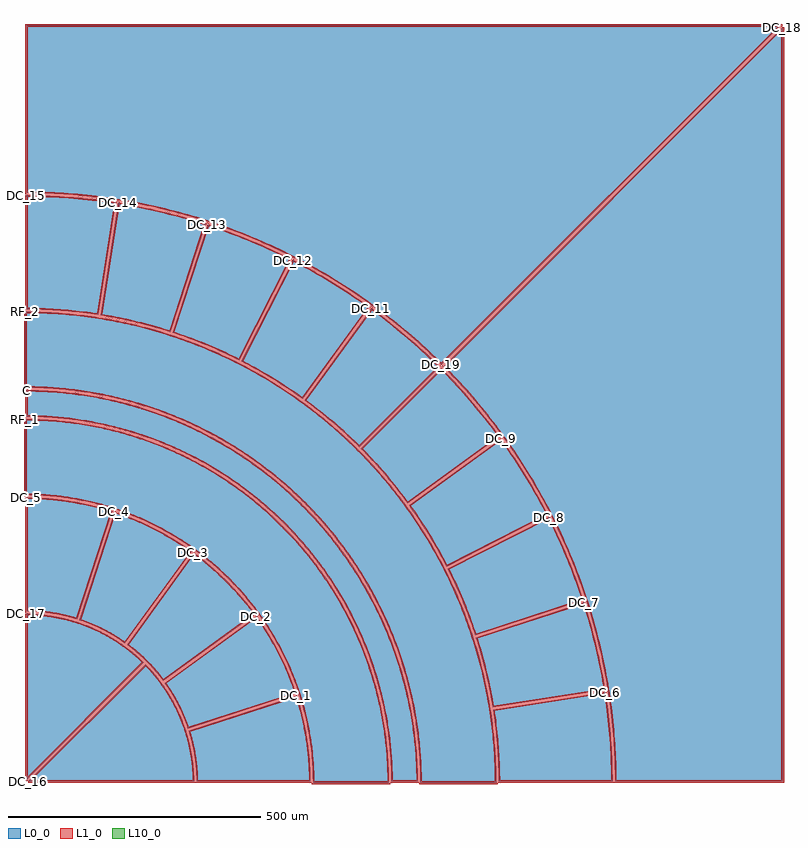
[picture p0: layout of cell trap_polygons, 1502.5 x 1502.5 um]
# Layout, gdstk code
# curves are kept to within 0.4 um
import gdstk
lib = gdstk.Library(unit=1e-6, precision=1e-09)
def P(c, l, *ps):  # polygons
    for p in ps: c.add(gdstk.Polygon(p, *l))
L0_0 = (0, 0)
L1_0 = (1, 0)
L10_0 = (10, 0)

trap_polygons = lib.new_cell('trap_polygons')
P(trap_polygons, L0_0, [(822.805,826.341),(782.779,864.352),(740.999,900.427),(712.217,923.36),(690.164,939.958),(644.909,971.565),(598.21,1000.996),(550.171,1028.183),(525.682,1040.916),(492.574,1056.986),(442.003,1079.111),(390.442,1098.819),(338.006,1116.064),(311.496,1123.752),(275.881,1133.021),(221.955,1144.807),(167.531,1154.028),(112.732,1160.663),(57.681,1164.698),(2.5,1166.122),(2.5,1497.5),(1493.964,1497.5)],
  [(1497.5,1493.964),(1497.5,2.5),(1166.122,2.5),(1164.698,57.681),(1160.663,112.732),(1154.028,167.531),(1144.807,221.955),(1133.021,275.881),(1123.752,311.496),(1116.064,338.006),(1098.819,390.442),(1079.111,442.003),(1056.986,492.574),(1040.916,525.682),(1028.183,550.171),(1000.996,598.21),(971.565,644.909),(939.958,690.164),(923.36,712.217),(900.427,740.999),(864.352,782.779),(826.341,822.805)],
  [(2.5,333.866),(33.622,332.178),(49.09,330.246),(66.998,327.084),(84.707,322.951),(99.689,318.645),(128.968,307.961),(157.123,294.593),(183.909,278.658),(209.092,260.294),(222.954,248.524),(234.311,237.846),(2.5,6.036)],
  [(6.036,2.5),(237.846,234.311),(248.524,222.954),(260.294,209.092),(278.658,183.909),(294.593,157.123),(307.961,128.968),(318.645,99.689),(322.951,84.707),(327.084,66.998),(330.246,49.09),(332.178,33.622),(333.866,2.5)],
  [(2.5,1161.122),(49.167,1160.084),(86.446,1157.903),(132.916,1153.492),(179.17,1147.218),(143.972,924.988),(106.932,929.998),(77.173,932.939),(39.869,935.276),(2.5,936.122)],
  [(184.109,1146.436),(220.88,1139.923),(266.518,1130.124),(311.725,1118.498),(356.429,1105.065),(286.9,891.077),(258.293,899.786),(222.167,909.38),(185.687,917.524),(148.911,924.205)],
  [(361.184,1103.52),(405.246,1088.112),(448.652,1070.945),(491.334,1052.047),(524.911,1035.703),(422.763,835.225),(389.083,851.437),(354.783,866.29),(319.918,879.763),(291.655,889.532)],
  [(529.366,1033.433),(570.475,1011.321),(602.701,992.453),(642.103,967.427),(680.468,940.837),(548.216,758.808),(517.487,780.088),(485.933,800.125),(460.129,815.237),(427.218,832.956)],
  [(684.513,937.898),(721.657,909.628),(757.634,879.888),(785.537,855.069),(819.27,822.805),(660.17,663.706),(638.635,684.453),(610.802,709.402),(581.996,733.22),(552.261,755.869)],
  [(822.805,819.27),(855.069,785.537),(879.888,757.634),(909.628,721.657),(937.898,684.513),(755.869,552.261),(733.22,581.996),(709.402,610.802),(684.453,638.635),(663.706,660.17)],
  [(940.837,680.468),(967.427,642.103),(992.453,602.701),(1011.321,570.475),(1033.433,529.366),(832.956,427.218),(815.237,460.129),(800.125,485.933),(780.088,517.487),(758.808,548.216)],
  [(1035.703,524.911),(1052.047,491.334),(1070.945,448.652),(1088.112,405.246),(1103.52,361.184),(889.532,291.655),(879.763,319.918),(866.29,354.783),(851.437,389.083),(835.225,422.763)],
  [(1105.065,356.429),(1118.498,311.725),(1130.124,266.518),(1139.923,220.88),(1146.436,184.109),(924.205,148.911),(917.524,185.687),(909.38,222.167),(899.786,258.293),(891.077,286.9)],
  [(1147.218,179.17),(1153.492,132.916),(1157.903,86.446),(1160.084,49.167),(1161.122,2.5),(936.122,2.5),(935.276,39.869),(932.939,77.173),(929.998,106.932),(924.988,143.972)],
  [(2.5,563.869),(42.187,562.295),(64.157,560.213),(86.029,557.274),(107.769,553.481),(129.344,548.84),(150.721,543.358),(171.868,537.044),(102.338,323.053),(77.26,329.95),(51.727,334.904),(25.889,337.885),(2.5,338.866)],
  [(176.623,535.499),(213.881,521.738),(234.132,512.969),(254.025,503.414),(273.53,493.089),(292.615,482.008),(311.251,470.189),(329.412,457.649),(197.158,275.618),(175.439,289.927),(155.004,301.347),(131.436,312.348),(107.093,321.508)],
  [(333.457,454.711),(350.994,441.314),(367.994,427.242),(397.156,400.277),(412.515,384.43),(427.242,367.994),(441.314,350.994),(454.711,333.457),(272.679,201.203),(258.137,219.548),(240.539,238.699),(221.523,256.444),(201.203,272.679)],
  [(457.649,329.412),(470.189,311.251),(482.008,292.615),(493.089,273.53),(503.414,254.025),(512.969,234.132),(521.738,213.881),(535.499,176.623),(321.508,107.093),(312.348,131.436),(301.347,155.004),(289.927,175.439),(275.618,197.158)],
  [(537.044,171.868),(543.358,150.721),(548.84,129.344),(553.481,107.769),(557.274,86.029),(560.213,64.157),(562.295,42.187),(563.869,2.5),(338.866,2.5),(337.885,25.889),(334.904,51.727),(329.95,77.26),(323.053,102.338)],
  [(2.5,776.121),(38.908,775.149),(75.23,772.47),(111.386,768.091),(153.253,760.844),(188.778,752.817),(223.887,743.132),(264.22,729.766),(298.165,716.567),(331.453,701.79),(364.011,685.468),(400.978,664.52),(431.711,644.977),(461.494,624.014),(490.261,601.676),(517.948,578.014),(548.803,548.803),(578.014,517.948),(601.676,490.261),(624.014,461.494),(644.977,431.711),(664.52,400.978),(685.468,364.011),(701.79,331.453),(716.567,298.165),(729.766,264.22),(743.132,223.887),(752.817,188.778),(760.844,153.253),(768.091,111.386),(772.47,75.23),(775.149,38.908),(776.121,2.5),(723.871,2.5),(722.957,36.446),(720.452,70.313),(716.362,104.024),(709.598,143.06),(702.108,176.182),(693.072,208.916),(680.605,246.521),(668.294,278.169),(654.513,309.206),(639.291,339.562),(622.662,369.171),(601.533,402.683),(581.985,430.451),(561.157,457.272),(535.299,487.288),(511.857,511.857),(487.288,535.299),(457.272,561.157),(430.451,581.985),(402.683,601.533),(369.171,622.662),(339.562,639.291),(309.206,654.513),(278.169,668.294),(246.521,680.605),(208.916,693.072),(176.182,702.108),(143.06,709.598),(104.024,716.362),(70.313,720.452),(36.446,722.957),(2.5,723.871)],
  [(0,931.125),(43.862,930.091),(87.627,926.993),(131.197,921.836),(181.653,913.234),(224.471,903.663),(266.79,892.086),(315.407,876.078),(356.326,860.247),(396.454,842.507),(442.151,819.449),(480.261,797.711),(517.305,774.202),(553.201,748.974),(593.521,717.444),(626.659,688.689),(658.405,658.405),(688.689,626.659),(717.444,593.521),(748.974,553.201),(774.202,517.305),(797.711,480.261),(819.449,442.151),(842.507,396.454),(860.247,356.326),(876.078,315.407),(892.086,266.79),(903.663,224.471),(913.234,181.653),(921.836,131.197),(926.993,87.627),(930.091,43.862),(931.125,0),(781.125,0),(779.945,42.923),(777.057,79.616),(772.444,116.132),(766.116,152.39),(758.087,188.31),(748.375,223.811),(737.001,258.816),(721.665,298.924),(706.783,332.587),(690.331,365.512),(672.347,397.625),(649.482,433.97),(628.318,464.083),(601.867,497.908),(577.744,525.707),(552.339,552.339),(525.707,577.744),(497.908,601.867),(464.083,628.318),(433.97,649.482),(397.625,672.347),(365.512,690.331),(332.587,706.783),(298.924,721.665),(258.816,737.001),(223.811,748.375),(188.31,758.087),(152.39,766.116),(116.132,772.444),(79.616,777.057),(42.923,779.945),(0,781.125)],
  [(0,718.875),(33.864,718.077),(67.652,715.685),(106.877,710.886),(140.246,705.062),(173.303,697.673),(205.975,688.735),(243.51,676.376),(275.102,664.154),(306.082,650.458),(341.362,632.656),(370.786,615.873),(399.386,597.723),(427.099,578.246),(453.864,557.485),(479.621,535.486),(508.321,508.321),(535.486,479.621),(557.485,453.864),(578.246,427.099),(597.723,399.386),(615.873,370.786),(632.656,341.362),(650.458,306.082),(664.154,275.102),(676.376,243.51),(688.735,205.975),(697.673,173.303),(705.062,140.246),(710.886,106.877),(715.685,67.652),(718.077,33.864),(718.875,0),(568.875,0),(568.436,22.334),(566.753,49.086),(564.389,71.299),(561.155,93.402),(557.055,115.361),(552.097,137.142),(545.024,162.997),(538.204,184.269),(528.927,209.417),(520.297,230.021),(508.884,254.275),(498.509,274.058),(487.365,293.418),(475.47,312.325),(460.23,334.376),(446.747,352.187),(426.719,376.204),(405.402,399.084),(379.544,423.752),(355.685,443.967),(330.751,462.842),(301.037,482.696),(274.058,498.509),(246.25,512.815),(213.565,527.266),(184.269,538.204),(154.416,547.517),(124.096,555.175),(93.402,561.155),(62.425,565.44),(31.26,568.015),(0,568.875)])
P(trap_polygons, L1_0, [(457.992,1075.133),(425.831,1088.279),(399.955,1098.053),(347.544,1115.75),(294.355,1130.946),(240.506,1143.609),(186.119,1153.709),(158.761,1157.791),(122.148,1162.224),(67.012,1166.702),(39.38,1167.961),(5,1168.607),(5,1495),(457.992,1495),(457.992,1500),(0,1500),(0,1163.637),(57.557,1162.201),(112.491,1158.175),(167.172,1151.554),(221.479,1142.353),(248.454,1136.791),(284.202,1128.385),(337.281,1113.672),(363.545,1105.377),(398.244,1093.355),(432.546,1080.244),(457.992,1069.704)],
  [(822.805,826.341),(824.573,824.573),(1497.5,1497.5),(1496.464,1500),(457.992,1500),(457.992,1495),(1487.929,1495),(822.794,829.866),(784.457,866.205),(742.588,902.357),(699.054,936.487),(653.954,968.519),(607.389,998.38),(559.463,1026.005),(510.283,1051.331),(457.992,1075.133),(457.992,1069.704),(508.1,1046.832),(557.069,1021.615),(604.79,994.109),(635.858,974.53),(658.745,959.207),(696.063,932.48),(732.298,904.302),(753.496,886.717),(781.101,862.499),(821.048,824.562)],
  [(1500,451.469),(1495,451.469),(1495,5),(1168.607,5),(1167.961,39.38),(1166.702,67.012),(1164.007,103.793),(1161.224,131.314),(1157.791,158.761),(1152.205,195.215),(1141.676,249.522),(1133.234,285.423),(1123.663,321.04),(1112.973,356.337),(1104.227,382.579),(1091.605,417.232),(1077.896,451.469),(1072.466,451.469),(1093.355,398.244),(1110.976,346.057),(1118.855,319.666),(1128.385,284.202),(1140.57,230.485),(1147.275,194.38),(1151.554,167.172),(1158.175,112.491),(1162.201,57.557),(1163.637,0),(1500,0)],
  [(1500,1493.964),(1497.501,1493.964),(1495.732,1495.732),(822.816,822.816),(862.499,781.101),(898.496,739.41),(932.48,696.063),(964.375,651.156),(994.109,604.79),(1021.615,557.069),(1046.832,508.1),(1058.565,483.181),(1072.466,451.469),(1077.896,451.469),(1059.252,493.63),(1043.148,526.809),(1026.005,559.463),(1012.476,583.589),(993.557,615.247),(978.717,638.59),(947.401,684.19),(925.34,713.744),(908.188,735.445),(872.367,777.599),(853.719,798.028),(829.866,822.795),(1495,1487.929),(1495,451.469),(1500,451.469)],
  [(237.846,237.846),(222.668,252.125),(206.551,265.49),(189.633,277.827),(174.224,287.74),(155.985,298.022),(134.746,308.207),(121.723,308.207),(151.377,294.779),(164.971,287.392),(180.374,277.983),(195.242,267.75),(207.526,258.345),(230.755,237.826),(5,12.071),(5,308.207),(0,308.207),(0,3.536),(2.5,2.5)],
  [(132.344,309.246),(115.31,315.993),(97.934,321.803),(80.267,326.658),(62.363,330.544),(41.677,333.783),(18.216,335.881),(2.528,336.365),(2.5,333.866),(0,333.866),(0,308.207),(5,308.207),(5,331.337),(30.803,329.94),(56.36,326.547),(74.056,322.994),(89.051,319.185),(106.298,313.863),(121.723,308.207),(134.746,308.207)],
  [(237.868,230.712),(258.345,207.526),(267.75,195.242),(277.983,180.374),(287.392,164.971),(294.779,151.377),(307.61,123.229),(307.61,136.097),(298.022,155.985),(287.74,174.224),(277.827,189.633),(265.49,206.551),(252.125,222.668),(237.846,237.846),(4.268,4.268),(6.036,2.499),(6.036,0),(307.61,0),(307.61,5),(12.071,5)],
  [(336.394,0.029),(335.881,18.216),(334.391,36.477),(332.324,52.045),(328.998,70.062),(325.369,85.342),(320.24,102.93),(314.16,120.214),(307.61,136.097),(307.61,123.229),(313.863,106.298),(318.483,91.533),(322.408,76.568),(326.098,58.9),(329.691,33.37),(331.337,5),(307.61,5),(307.61,0)],
  [(2.515,1163.622),(2.485,1158.622),(49.061,1157.586),(86.26,1155.409),(132.63,1151.009),(176.308,1145.125),(141.892,927.831),(107.217,932.481),(77.38,935.43),(39.975,937.773),(5,938.605),(5,1161.122),(0,1161.122),(0,933.638),(32.311,933.066),(69.534,931.032),(106.646,927.514),(146.053,922.144),(182.031,1149.296),(142.492,1154.868),(95.96,1159.662),(49.272,1162.581)],
  [(184.515,1148.903),(183.702,1143.969),(220.404,1137.468),(265.944,1127.69),(311.054,1116.09),(353.274,1103.446),(285.29,894.212),(251.769,904.228),(215.471,913.558),(186.183,919.974),(151.769,926.267),(186.578,1146.045),(181.64,1146.827),(146.053,922.144),(177.877,916.523),(214.324,908.692),(250.428,899.412),(288.51,887.943),(359.579,1106.671),(321.399,1118.359),(276.19,1130.373),(230.534,1140.56)],
  [(361.971,1105.893),(360.397,1101.148),(404.373,1085.769),(439.08,1072.204),(481.819,1053.69),(521.541,1034.596),(421.663,838.573),(390.122,853.71),(355.731,868.604),(327.806,879.523),(294.8,891.121),(363.562,1102.748),(358.807,1104.293),(288.51,887.943),(319.063,877.413),(353.836,863.977),(388.044,849.163),(423.863,831.878),(528.273,1036.795),(492.392,1054.312),(449.618,1073.25),(406.118,1090.455)],
  [(530.515,1035.653),(528.217,1031.212),(561.114,1013.688),(601.403,990.316),(640.721,965.344),(676.967,940.272),(547.653,762.286),(518.869,782.171),(493.622,798.345),(461.358,817.414),(430.573,834.033),(531.594,1032.298),(527.138,1034.568),(423.863,831.878),(458.901,813.06),(490.993,794.092),(522.302,773.858),(548.779,755.329),(683.96,941.39),(651.261,964.304),(611.976,989.701),(571.703,1013.498)],
  [(685.995,939.912),(683.031,935.885),(720.103,907.669),(748.919,884.043),(783.846,853.228),(815.723,822.794),(660.158,667.23),(634.839,691.373),(606.733,716.165),(583.55,735.178),(555.743,756.409),(686.536,936.429),(682.491,939.368),(548.779,755.329),(574.583,735.874),(603.501,712.35),(631.458,687.69),(660.182,660.182),(822.805,822.805),(794.093,850.553),(759.265,881.782),(723.21,911.586)],
  [(824.584,821.027),(821.027,817.513),(846.898,790.681),(877.993,756.003),(907.669,720.103),(934.394,685.057),(756.409,555.743),(735.178,583.55),(716.165,606.733),(691.373,634.839),(667.23,660.158),(824.573,817.502),(821.037,821.037),(660.182,660.182),(687.69,631.458),(712.35,603.501),(735.874,574.583),(755.329,548.779),(941.39,683.96),(917.372,715.857),(887.858,752.151),(856.91,787.228)],
  [(942.869,681.925),(938.806,679.011),(965.344,640.721),(985.448,609.347),(1009.143,569.246),(1030.056,530.452),(834.033,430.573),(817.414,461.358),(798.345,493.622),(782.171,518.869),(762.286,547.653),(942.307,678.445),(939.368,682.491),(755.329,548.779),(773.858,522.302),(794.092,490.993),(813.06,458.901),(831.878,423.863),(1036.795,528.273),(1018.062,563.535),(994.59,603.999),(969.51,643.486)],
  [(1037.937,526.032),(1033.468,523.79),(1053.69,481.819),(1068.639,447.686),(1085.769,404.373),(1100.355,362.784),(891.121,294.8),(879.523,327.806),(868.604,355.731),(853.71,390.122),(838.573,421.663),(1036.838,522.683),(1034.568,527.138),(831.878,423.863),(849.163,388.044),(863.977,353.836),(877.413,319.063),(887.943,288.51),(1106.671,359.579),(1093.685,397.337),(1076.831,440.974),(1058.237,483.899)],
  [(1107.448,357.187),(1102.683,355.671),(1113.553,320.018),(1125.516,275.003),(1135.659,229.543),(1143.56,186.184),(926.267,151.769),(919.974,186.183),(913.558,215.471),(904.228,251.769),(894.212,285.29),(1105.838,354.051),(1104.293,358.807),(887.943,288.51),(899.412,250.428),(908.692,214.324),(916.523,177.877),(922.144,146.053),(1149.296,182.031),(1142.377,221.355),(1132.557,267.092),(1120.907,312.396)],
  [(1149.69,179.546),(1144.746,178.794),(1151.009,132.63),(1154.679,95.548),(1157.586,49.061),(1158.607,5),(938.605,5),(937.773,39.975),(935.43,77.38),(932.481,107.217),(927.831,141.892),(1147.609,176.701),(1146.827,181.64),(922.144,146.053),(927.514,106.646),(931.032,69.534),(933.066,32.311),(933.638,0),(1163.622,0),(1162.94,39.923),(1160.396,86.632),(1155.976,133.202)],
  [(2.521,566.369),(2.479,561.37),(42,559.802),(63.873,557.729),(85.648,554.803),(107.291,551.027),(128.771,546.406),(168.711,535.419),(100.724,326.177),(77.83,332.384),(54.697,336.965),(28.692,340.167),(5,341.338),(5,563.869),(0,563.869),(0,336.394),(28.272,335.185),(53.896,332.029),(79.202,326.918),(103.951,319.929),(175.018,538.649),(134.229,550.239),(112.596,555.07),(90.789,559.051),(68.844,562.175),(46.794,564.439),(24.671,565.837)],
  [(177.415,537.87),(175.831,533.128),(196.566,525.836),(216.992,517.742),(252.899,501.182),(272.317,490.903),(291.317,479.871),(325.907,457.079),(196.588,279.087),(176.733,292.066),(153.812,304.76),(132.405,314.652),(110.234,323.087),(179.001,534.727),(174.245,536.272),(103.951,319.929),(130.466,310.043),(153.86,299.124),(176.349,286.443),(197.727,272.148),(332.904,458.203),(297.693,481.829),(278.611,493.109),(259.102,503.634),(239.196,513.387),(218.924,522.353),(198.317,530.52)],
  [(334.943,456.721),(331.97,452.7),(363.022,428.202),(379.499,413.669),(395.395,398.503),(410.686,382.726),(425.347,366.362),(451.202,333.997),(273.209,204.678),(258.336,223.158),(242.313,240.46),(223.158,258.336),(204.678,273.209),(335.479,453.241),(331.434,456.18),(197.727,272.148),(217.928,256.233),(236.938,238.764),(254.552,219.889),(272.148,197.727),(458.203,332.904),(432.016,366.255),(417.354,382.879),(402.052,398.917),(386.135,414.344),(369.625,429.136),(352.55,443.271)],
  [(459.684,330.864),(455.615,327.959),(477.576,295.065),(488.756,276.151),(499.187,256.815),(508.854,237.085),(517.742,216.992),(532.329,178.222),(323.087,110.234),(314.652,132.405),(304.76,153.812),(292.066,176.733),(279.087,196.588),(459.119,327.389),(456.18,331.434),(272.148,197.727),(286.443,176.349),(299.124,153.86),(310.043,130.466),(319.929,103.951),(538.649,175.018),(524.051,214.829),(515.243,235.17),(505.646,255.152),(495.275,274.742),(484.145,293.912),(472.273,312.631)],
  [(539.428,172.62),(534.66,171.115),(545.382,133.044),(550.17,111.602),(554.116,89.988),(557.212,68.236),(559.456,46.38),(561.349,5),(341.338,5),(340.167,28.692),(336.965,54.697),(332.384,77.83),(326.177,100.724),(537.817,169.49),(536.272,174.245),(319.929,103.951),(326.918,79.202),(332.029,53.896),(335.185,28.272),(336.394,0),(566.369,0),(564.788,42.374),(562.697,64.441),(559.744,86.41),(555.935,108.247),(551.273,129.918),(545.767,151.39)],
  [(229.692,689.098),(204.193,697.084),(176.79,704.532),(149.117,710.904),(121.216,716.19),(93.129,720.38),(64.9,723.47),(36.572,725.454),(5,726.352),(5,773.603),(50.864,771.951),(99.037,767.26),(128.961,762.801),(164.604,755.911),(199.885,747.356),(229.692,738.738),(229.692,743.972),(195.288,753.737),(165.668,760.796),(135.795,766.692),(105.714,771.415),(69.408,775.525),(32.949,777.928),(2.518,778.621),(2.5,776.121),(0,776.121),(0,721.389),(47.583,719.804),(70.07,717.964),(98.079,714.676),(131.489,709.29),(164.61,702.343),(197.368,693.85),(229.692,683.83)],
  [(440.325,642.154),(417.801,657.038),(391.792,672.871),(365.184,687.676),(338.017,701.428),(310.334,714.108),(282.176,725.695),(253.586,736.173),(229.692,743.972),(229.692,738.738),(263.369,727.415),(291.608,716.561),(319.402,704.612),(352.106,688.852),(394.493,665.485),(415.118,652.819),(440.325,636.089)],
  [(440.325,577.694),(413.464,597.217),(389.804,612.922),(365.549,627.69),(340.735,641.499),(315.4,654.327),(284.365,668.399),(258.022,679.003),(229.692,689.098),(229.692,683.83),(261.511,672.305),(292.754,659.3),(323.353,644.845),(353.24,628.97),(372.736,617.616),(396.593,602.575),(419.842,586.612),(440.325,571.391)],
  [(605.657,489.313),(587.933,510.481),(567.525,533.079),(546.248,554.861),(528.623,571.677),(505.867,591.908),(487.104,607.443),(462.981,626.024),(440.325,642.154),(440.325,636.089),(464.859,618.387),(493.357,595.898),(516.279,576.152),(538.411,555.526),(572.096,520.77),(588.107,502.619),(605.657,481.317)],
  [(605.657,400.989),(587.355,427.358),(570.202,449.99),(552.177,471.934),(529.436,497.311),(505.53,521.594),(484.756,540.955),(463.241,559.49),(440.325,577.694),(440.325,571.391),(464.383,552.024),(489.761,529.637),(514.062,506.085),(537.232,481.419),(555.638,460.052),(573.196,437.982),(589.877,415.243),(605.657,391.869)],
  [(709.166,321.467),(687.676,365.184),(663.494,407.472),(636.714,448.165),(622.383,467.863),(605.657,489.313),(605.657,481.317),(622.004,460.008),(639.514,435.336),(656.046,409.999),(671.575,384.035),(691.585,346.707),(709.166,309.152)],
  [(709.166,157.148),(701.682,187.786),(692.102,220.488),(681,252.705),(668.399,284.365),(654.327,315.4),(638.815,345.74),(621.897,375.32),(605.657,400.989),(605.657,391.869),(626.189,358.147),(642.297,328.385),(656.991,297.9),(672.305,261.511),(683.83,229.692),(693.85,197.368),(702.343,164.61),(709.166,132.144)],
  [(778.639,0.018),(777.646,39.033),(774.345,81.531),(768.722,123.785),(760.796,165.668),(752.187,201.177),(740.05,242.039),(725.695,282.176),(709.166,321.467),(709.166,309.152),(723.206,274.715),(735.298,240.485),(745.77,205.725),(755.911,164.604),(762.801,128.961),(767.26,99.037),(771.061,62.933),(773.164,26.691),(773.603,5),(726.352,5),(725.146,42.244),(721.748,81.852),(716.19,121.216),(709.166,157.148),(709.166,132.144),(715.421,92.488),(719.41,53.21),(720.94,25.049),(721.389,0)],
  [(259.078,739.557),(224.528,750.77),(194.88,759.006),(164.931,766.072),(134.728,771.956),(104.317,776.651),(67.616,780.702),(36.914,782.755),(2.5,783.615),(2.5,928.615),(29.169,928.167),(58.309,926.793),(87.391,924.504),(116.388,921.302),(152.468,916.023),(188.313,909.331),(223.868,901.237),(259.078,891.753),(259.078,896.953),(225.074,906.089),(189.327,914.227),(160.517,919.723),(124.285,925.316),(87.862,929.482),(43.98,932.589),(0.01,933.625),(0,931.125),(-2.5,931.125),(-2.5,778.635),(24.457,778.241),(54.992,776.681),(85.442,773.923),(115.76,769.972),(151.902,763.664),(187.707,755.661),(223.095,745.979),(259.078,734.254)],
  [(497.582,789.971),(468.928,807.318),(443.338,821.649),(410.738,838.421),(384.2,850.909),(350.497,865.337),(323.144,875.919),(288.506,887.93),(259.078,896.953),(259.078,891.753),(293.888,880.894),(328.246,868.677),(362.097,855.12),(395.389,840.245),(421.587,827.411),(447.368,813.76),(472.709,799.307),(497.582,784.064)],
  [(497.582,605.368),(470.504,626.653),(440.463,648.121),(414.678,664.914),(382.896,683.71),(350.264,700.988),(322.473,714.198),(288.472,728.596),(259.078,739.557),(259.078,734.254),(292.308,721.674),(320.415,709.641),(348.029,696.515),(380.453,679.347),(412.032,660.671),(442.696,640.528),(472.378,618.964),(497.582,598.884)],
  [(682.314,637.252),(660.173,660.173),(639.11,680.583),(617.417,700.322),(595.115,719.37),(572.225,737.708),(548.771,755.319),(524.775,772.183),(497.582,789.971),(497.582,784.064),(527.981,763.925),(551.716,746.963),(580.616,724.727),(608.621,701.374),(646.242,666.87),(682.314,629.911)],
  [(682.314,385.365),(664.914,414.678),(644.642,445.539),(622.938,475.411),(599.852,504.228),(575.433,531.925),(549.738,558.441),(522.821,583.718),(497.582,605.368),(497.582,598.884),(524.024,575.895),(550.571,550.571),(571.762,528.531),(596.024,501.011),(618.964,472.378),(643.986,437.652),(663.887,406.83),(682.314,375.105)],
  [(780.331,512.581),(755.319,548.771),(733.192,578.002),(709.934,606.341),(682.314,637.252),(682.314,629.911),(710.847,597.529),(733.758,569.161),(759.754,533.964),(780.331,503.414)],
  [(780.331,71.714),(775.807,110.414),(768.568,152.878),(759.006,194.88),(747.151,236.293),(733.037,276.992),(719.175,311.215),(700.988,350.264),(682.314,385.365),(682.314,375.105),(696.515,348.029),(707.103,325.979),(719.356,297.967),(730.499,269.495),(744.204,228.947),(755.661,187.707),(765.956,139.888),(773.228,91.518),(777.449,42.786),(778.635,-2.5),(780.331,-2.5)],
  [(933.635,-2.49),(933.164,29.326),(931.294,65.939),(927.987,102.451),(924.311,131.549),(918.434,167.736),(912.712,196.502),(904.293,232.183),(894.481,267.506),(885.637,295.471),(873.354,330.013),(859.724,364.046),(844.769,397.518),(831.866,423.857),(814.584,456.189),(799.853,481.551),(780.331,512.581),(780.331,503.414),(799.307,472.709),(817.249,440.964),(833.931,408.539),(849.327,375.484),(860.702,348.62),(871.228,321.413),(883.175,286.961),(891.753,259.078),(899.451,230.94),(907.824,195.449),(913.515,166.837),(919.361,130.844),(923.789,94.65),(926.306,65.586),(927.909,36.458),(928.615,2.5),(783.615,2.5),(782.755,36.914),(780.331,71.714),(780.331,-2.5)],
  [(193.546,537.596),(172.291,544.78),(146.437,552.291),(120.258,558.576),(98.236,562.867),(71.612,566.87),(49.302,569.244),(26.915,570.741),(2.5,571.365),(2.5,716.365),(28.125,715.823),(50.595,714.586),(78.611,712.049),(100.938,709.228),(145.272,701.491),(167.234,696.581),(193.546,689.731),(193.546,694.92),(168.402,701.443),(140.733,707.514),(112.848,712.494),(84.789,716.375),(50.949,719.574),(22.659,721.019),(0.01,721.375),(0,718.875),(-2.5,718.875),(-2.5,566.385),(40.001,564.961),(62.151,562.955),(84.204,560.081),(114.854,554.607),(140.852,548.581),(166.537,541.337),(193.546,532.274)],
  [(371.202,618.536),(347.525,632.146),(327.497,642.75),(286.493,662.045),(265.556,670.718),(239.019,680.626),(193.546,694.92),(193.546,689.731),(237.362,675.909),(263.715,666.069),(284.507,657.456),(310.099,645.78),(330.231,635.721),(371.202,612.695)],
  [(371.202,434.37),(353.735,448.71),(332.205,464.876),(309.938,480.008),(286.982,494.076),(267.363,504.962),(243.28,516.996),(218.656,527.882),(193.546,537.596),(193.546,532.274),(220.845,521.544),(249.171,508.62),(276.743,494.16),(299.714,480.575),(318.35,468.438),(336.495,455.578),(354.122,442.016),(371.202,427.773)],
  [(507.046,513.109),(477.054,541.111),(442.136,569.998),(405.473,596.635),(371.202,618.536),(371.202,612.695),(407.303,589.319),(443.503,562.581),(477.953,533.623),(507.046,506.058)],
  [(507.046,263.389),(494.076,286.982),(480.008,309.938),(464.876,332.205),(448.71,353.735),(431.549,374.479),(413.43,394.392),(394.392,413.43),(371.202,434.37),(371.202,427.773),(394.148,406.729),(415.902,384.456),(433.551,364.437),(452.921,340.063),(468.438,318.35),(482.914,295.93),(496.318,272.853),(507.046,252.353)],
  [(583.605,424.014),(566.508,446.599),(548.538,468.496),(529.722,489.67),(507.046,513.109),(507.046,506.058),(529.853,482.129),(548.373,460.956),(566.047,439.071),(583.605,415.443)],
  [(583.605,2.5),(571.365,2.5),(570.248,35.877),(566.87,71.612),(562.078,102.654),(554.523,137.744),(544.78,172.291),(534.489,201.967),(522.584,231.032),(507.046,263.389),(507.046,252.353),(521.544,220.845),(534.382,187.661),(545.111,153.737),(552.735,123.551),(558.689,92.991),(562.955,62.151),(565.519,31.122),(566.385,-2.5),(583.605,-2.5)],
  [(721.385,-2.49),(720.819,28.321),(719.151,56.598),(716.375,84.789),(712.494,112.848),(707.514,140.733),(701.443,168.402),(694.291,195.81),(686.068,222.917),(676.788,249.68),(666.464,276.058),(655.112,302.011),(642.75,327.497),(629.397,352.479),(615.073,376.917),(599.801,400.774),(583.605,424.014),(583.605,415.443),(601.822,388.592),(616.614,364.665),(633.108,335.213),(645.78,310.099),(655.202,289.662),(666.069,263.715),(675.909,237.362),(683.031,216.014),(690.985,189.032),(697.873,161.758),(702.61,139.758),(707.555,112.066),(711.409,84.201),(714.167,56.206),(715.823,28.125),(716.365,2.5),(583.605,2.5),(583.605,-2.5)])
P(trap_polygons, L10_0, [(0,0),(0,0),(0,0),(0,0)])
trap_polygons.add(gdstk.Label('DC_19', (822.805,826.341), layer=2, texttype=0))
trap_polygons.add(gdstk.Label('DC_18', (1497.5,1493.964), layer=2, texttype=0))
trap_polygons.add(gdstk.Label('DC_17', (2.5,333.866), layer=2, texttype=0))
trap_polygons.add(gdstk.Label('DC_16', (6.036,2.5), layer=2, texttype=0))
trap_polygons.add(gdstk.Label('DC_15', (2.5,1161.122), layer=2, texttype=0))
trap_polygons.add(gdstk.Label('DC_14', (184.109,1146.436), layer=2, texttype=0))
trap_polygons.add(gdstk.Label('DC_13', (361.184,1103.52), layer=2, texttype=0))
trap_polygons.add(gdstk.Label('DC_12', (529.366,1033.433), layer=2, texttype=0))
trap_polygons.add(gdstk.Label('DC_11', (684.513,937.898), layer=2, texttype=0))
trap_polygons.add(gdstk.Label('DC_10', (822.805,819.27), layer=2, texttype=0))
trap_polygons.add(gdstk.Label('DC_9', (940.837,680.468), layer=2, texttype=0))
trap_polygons.add(gdstk.Label('DC_8', (1035.703,524.911), layer=2, texttype=0))
trap_polygons.add(gdstk.Label('DC_7', (1105.065,356.429), layer=2, texttype=0))
trap_polygons.add(gdstk.Label('DC_6', (1147.218,179.17), layer=2, texttype=0))
trap_polygons.add(gdstk.Label('DC_5', (2.5,563.869), layer=2, texttype=0))
trap_polygons.add(gdstk.Label('DC_4', (176.623,535.499), layer=2, texttype=0))
trap_polygons.add(gdstk.Label('DC_3', (333.457,454.711), layer=2, texttype=0))
trap_polygons.add(gdstk.Label('DC_2', (457.649,329.412), layer=2, texttype=0))
trap_polygons.add(gdstk.Label('DC_1', (537.044,171.868), layer=2, texttype=0))
trap_polygons.add(gdstk.Label('C', (2.5,776.121), layer=2, texttype=0))
trap_polygons.add(gdstk.Label('RF_2', (0,931.125), layer=2, texttype=0))
trap_polygons.add(gdstk.Label('RF_1', (0,718.875), layer=2, texttype=0))

lib.write_gds('trap_polygons.gds')
